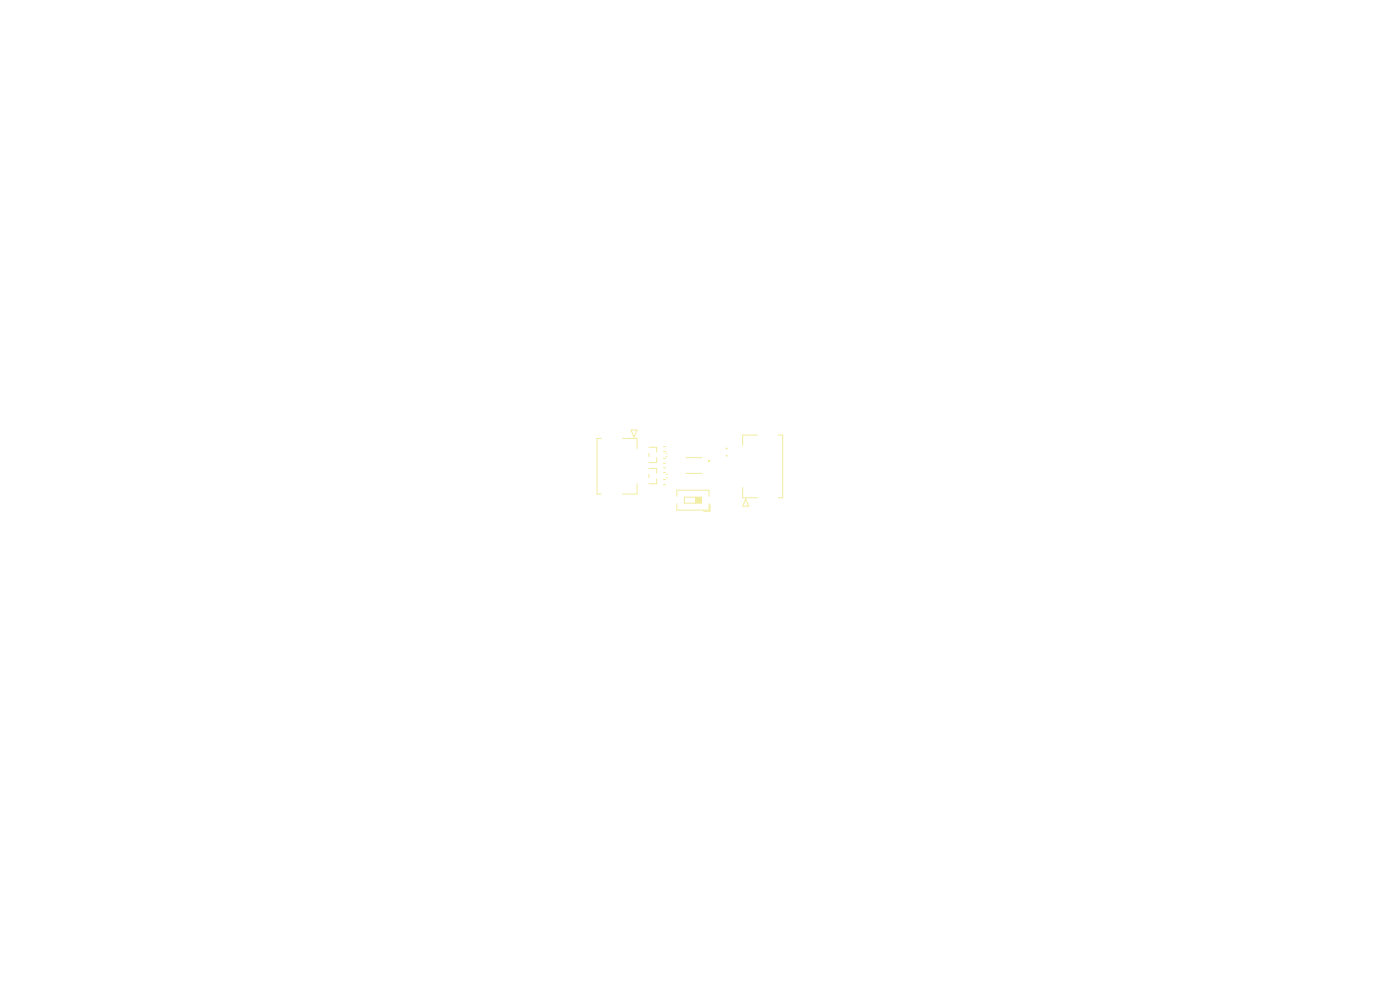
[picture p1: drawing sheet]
<svg xmlns="http://www.w3.org/2000/svg" width="297mm" height="210mm" viewBox="0 0 297 210" stroke-linecap="round" stroke-linejoin="round" font-family="sans-serif">
<g fill="none" stroke="#f2eda1" stroke-width=".21">
<path d="M137.7 96.2v.7M137.7 94.9h1.6v1M139.3 97.1v1h-1.6M140.7 97.2h.5M140.7 98.3h.5M140.7 94.7h.5M140.7 95.8h.5M145.5 97.1h3.4M141.4 100.6h.2M141.4 101.4h.2M143.6 105.3v-1.3h6.8v1.3M143.6 106.9v1.3h6.8v-1.3"/>
<path d="M145.2 105.5h3.6v1.2h-3.6zM145.5 100.4h3.4M147.6 105.5v1.2M147.6 105.5h1.2M147.6 105.7h1.2M147.6 105.8h1.2M147.6 105.9h1.2M147.6 106h1.2M147.6 106.1h1.2M147.6 106.3h1.2M147.6 106.4h1.2M147.6 106.5h1.2"/>
<path d="M147.6 106.6h1.2M150.6 107.1v1.4h-1.3"/>
<circle cx="154.2" cy="96.7" r=".1"/>
</g>
<path d="M150.3 97.6h.3v.3h-.3z" fill="#f2eda1"/>
<g fill="none" stroke="#f2eda1" stroke-width=".21">
<path d="M127.6 93h-1v11.8h1M132 93h3.2v2.2M133.9 91.2h1.2l-.6 1.5zM137.7 99.4h1.6v1M140.7 99.2h.5M141.3 96.1h.2M141.3 96.9h.2M160.7 92.3h-3.1v2.2M165.1 92.3h.9v13.3h-.9M135.2 102.6v2.2h-3.2M137.7 100.6v.8M139.3 101.6v1h-1.6"/>
<path d="M140.7 101.7h.5M140.7 102.8h.5M140.7 100.3h.5M157.6 103.4v2.2h3.1M158.2 105.8l.6 1.6h-1.2z"/>
<circle cx="154.1" cy="95.2" r=".1"/>
</g>
</svg>
